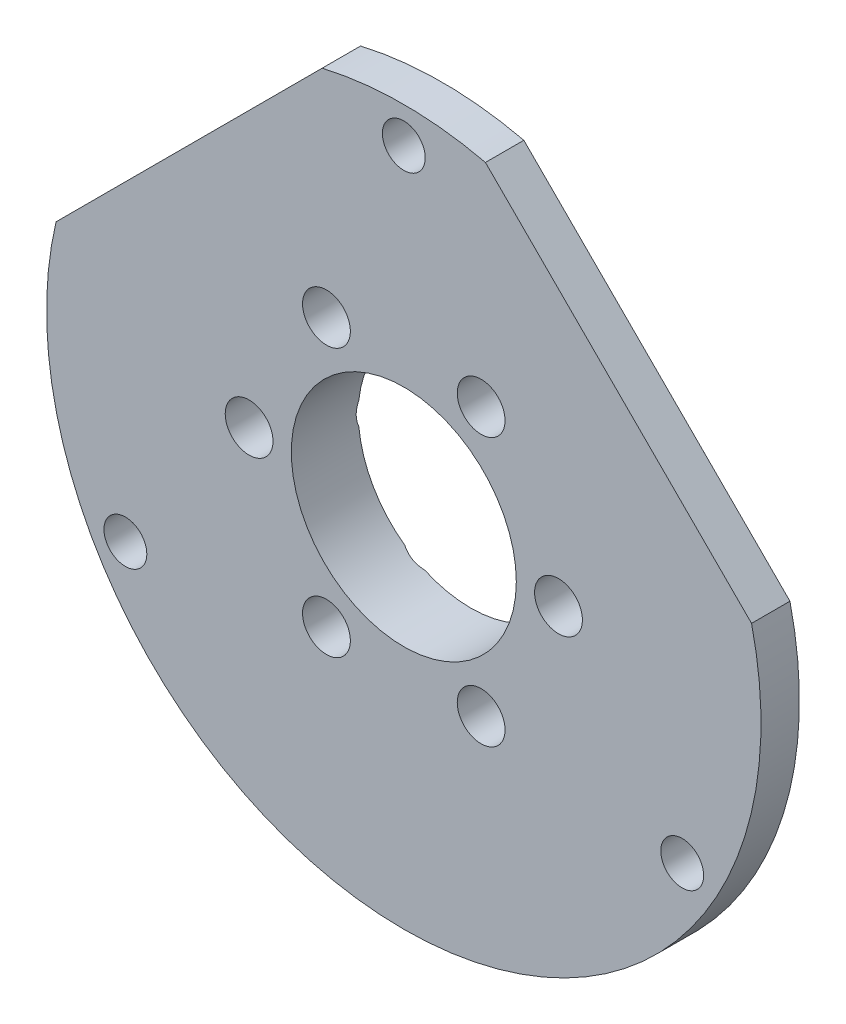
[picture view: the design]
ISO-10303-21;
HEADER;
FILE_DESCRIPTION(('STEP AP214'),'2;1');
FILE_NAME('part.step','',(''),(''),'','','');
FILE_SCHEMA(('AUTOMOTIVE_DESIGN { 1 0 10303 214 1 1 1 1 }'));
ENDSEC;
DATA;
#1=APPLICATION_CONTEXT('core data for automotive mechanical design processes');
#2=APPLICATION_PROTOCOL_DEFINITION('international standard','automotive_design',2000,#1);
#3=PRODUCT_CONTEXT('',#1,'mechanical');
#4=PRODUCT('Part','Part','',(#3));
#5=PRODUCT_RELATED_PRODUCT_CATEGORY('part','',(#4));
#6=PRODUCT_DEFINITION_FORMATION('','',#4);
#7=PRODUCT_DEFINITION_CONTEXT('part definition',#1,'design');
#8=PRODUCT_DEFINITION('design','',#6,#7);
#9=PRODUCT_DEFINITION_SHAPE('','',#8);
#10=(LENGTH_UNIT() NAMED_UNIT(*) SI_UNIT(.MILLI.,.METRE.));
#11=(NAMED_UNIT(*) PLANE_ANGLE_UNIT() SI_UNIT($,.RADIAN.));
#12=(NAMED_UNIT(*) SI_UNIT($,.STERADIAN.) SOLID_ANGLE_UNIT());
#13=UNCERTAINTY_MEASURE_WITH_UNIT(LENGTH_MEASURE(1.E-05),#10,'distance_accuracy_value','');
#14=(GEOMETRIC_REPRESENTATION_CONTEXT(3) GLOBAL_UNCERTAINTY_ASSIGNED_CONTEXT((#13)) GLOBAL_UNIT_ASSIGNED_CONTEXT((#10,
#11,#12)) REPRESENTATION_CONTEXT('',''));
#15=CARTESIAN_POINT('',(0.,0.,0.));
#16=DIRECTION('',(0.,0.,1.));
#17=DIRECTION('',(1.,0.,0.));
#18=AXIS2_PLACEMENT_3D('',#15,#16,#17);
#19=CARTESIAN_POINT('',(0.,0.,4.7625));
#20=DIRECTION('',(0.,0.,-1.));
#21=DIRECTION('',(-1.,0.,0.));
#22=AXIS2_PLACEMENT_3D('',#19,#20,#21);
#23=CYLINDRICAL_SURFACE('',#22,25.4);
#24=CARTESIAN_POINT('',(0.,0.,4.7625));
#25=DIRECTION('',(0.,0.,1.));
#26=DIRECTION('',(1.,0.,0.));
#27=AXIS2_PLACEMENT_3D('',#24,#25,#26);
#28=CIRCLE('',#27,25.4);
#29=CARTESIAN_POINT('',(-24.7277223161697,5.8051484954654,4.7625));
#30=VERTEX_POINT('',#29);
#31=CARTESIAN_POINT('',(24.7277223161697,5.8051484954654,4.7625));
#32=VERTEX_POINT('',#31);
#33=EDGE_CURVE('E136',#30,#32,#28,.T.);
#34=ORIENTED_EDGE('',*,*,#33,.F.);
#35=DIRECTION('',(0.,0.,-1.));
#36=VECTOR('',#35,1.);
#37=CARTESIAN_POINT('',(-24.7277223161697,5.80514849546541,4.7625));
#38=LINE('',#37,#36);
#39=CARTESIAN_POINT('',(-24.7277223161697,5.80514849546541,2.032));
#40=VERTEX_POINT('',#39);
#41=EDGE_CURVE('E120',#30,#40,#38,.T.);
#42=ORIENTED_EDGE('',*,*,#41,.T.);
#43=CARTESIAN_POINT('',(0.,0.,2.032));
#44=DIRECTION('',(0.,0.,-1.));
#45=DIRECTION('',(-1.,0.,0.));
#46=AXIS2_PLACEMENT_3D('',#43,#44,#45);
#47=CIRCLE('',#46,25.4);
#48=CARTESIAN_POINT('',(24.7277223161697,5.80514849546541,2.032));
#49=VERTEX_POINT('',#48);
#50=EDGE_CURVE('E198',#49,#40,#47,.T.);
#51=ORIENTED_EDGE('',*,*,#50,.F.);
#52=DIRECTION('',(0.,0.,-1.));
#53=VECTOR('',#52,1.);
#54=CARTESIAN_POINT('',(24.7277223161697,5.80514849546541,4.7625));
#55=LINE('',#54,#53);
#56=EDGE_CURVE('E66',#49,#32,#55,.F.);
#57=ORIENTED_EDGE('',*,*,#56,.T.);
#58=EDGE_LOOP('',(#34,#42,#51,#57));
#59=FACE_BOUND('',#58,.T.);
#60=ADVANCED_FACE('F43',(#59),#23,.T.);
#61=CARTESIAN_POINT('',(-5.8051484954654,24.7277223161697,2.032));
#62=VERTEX_POINT('',#61);
#63=CARTESIAN_POINT('',(5.8051484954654,24.7277223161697,2.032));
#64=VERTEX_POINT('',#63);
#65=EDGE_CURVE('E195',#62,#64,#47,.T.);
#66=ORIENTED_EDGE('',*,*,#65,.F.);
#67=DIRECTION('',(0.,0.,-1.));
#68=VECTOR('',#67,1.);
#69=CARTESIAN_POINT('',(-5.8051484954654,24.7277223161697,4.7625));
#70=LINE('',#69,#68);
#71=CARTESIAN_POINT('',(-5.8051484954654,24.7277223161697,4.7625));
#72=VERTEX_POINT('',#71);
#73=EDGE_CURVE('E58',#62,#72,#70,.F.);
#74=ORIENTED_EDGE('',*,*,#73,.T.);
#75=CARTESIAN_POINT('',(5.8051484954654,24.7277223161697,4.7625));
#76=VERTEX_POINT('',#75);
#77=EDGE_CURVE('E138',#76,#72,#28,.T.);
#78=ORIENTED_EDGE('',*,*,#77,.F.);
#79=DIRECTION('',(0.,0.,-1.));
#80=VECTOR('',#79,1.);
#81=CARTESIAN_POINT('',(5.8051484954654,24.7277223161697,4.7625));
#82=LINE('',#81,#80);
#83=EDGE_CURVE('E196',#76,#64,#82,.T.);
#84=ORIENTED_EDGE('',*,*,#83,.T.);
#85=EDGE_LOOP('',(#66,#74,#78,#84));
#86=FACE_BOUND('',#85,.T.);
#87=ADVANCED_FACE('F45',(#86),#23,.T.);
#88=CARTESIAN_POINT('',(0.,0.,0.));
#89=DIRECTION('',(0.,0.,1.));
#90=DIRECTION('',(1.,0.,0.));
#91=AXIS2_PLACEMENT_3D('',#88,#89,#90);
#92=PLANE('',#91);
#93=CARTESIAN_POINT('',(0.,0.,0.));
#94=DIRECTION('',(0.,0.,1.));
#95=DIRECTION('',(1.,0.,0.));
#96=AXIS2_PLACEMENT_3D('',#93,#94,#95);
#97=CIRCLE('',#96,17.907);
#98=CARTESIAN_POINT('',(17.907,0.,0.));
#99=VERTEX_POINT('',#98);
#100=EDGE_CURVE('E51',#99,#99,#97,.F.);
#101=ORIENTED_EDGE('',*,*,#100,.T.);
#102=EDGE_LOOP('',(#101));
#103=FACE_BOUND('',#102,.T.);
#104=CARTESIAN_POINT('',(0.,0.,0.));
#105=DIRECTION('',(0.,0.,1.));
#106=DIRECTION('',(1.,0.,0.));
#107=AXIS2_PLACEMENT_3D('',#104,#105,#106);
#108=CIRCLE('',#107,8.);
#109=CARTESIAN_POINT('',(-4.68745706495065,6.48288101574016,0.));
#110=VERTEX_POINT('',#109);
#111=CARTESIAN_POINT('',(-7.95806818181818,0.818016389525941,0.));
#112=VERTEX_POINT('',#111);
#113=EDGE_CURVE('E394',#110,#112,#108,.T.);
#114=ORIENTED_EDGE('',*,*,#113,.T.);
#115=CARTESIAN_POINT('',(-11.,0.,0.));
#116=DIRECTION('',(0.,0.,-1.));
#117=DIRECTION('',(-1.,0.,0.));
#118=AXIS2_PLACEMENT_3D('',#115,#116,#117);
#119=CIRCLE('',#118,3.15);
#120=CARTESIAN_POINT('',(-7.95806818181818,-0.818016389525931,0.));
#121=VERTEX_POINT('',#120);
#122=EDGE_CURVE('E201',#121,#112,#119,.T.);
#123=ORIENTED_EDGE('',*,*,#122,.F.);
#124=CARTESIAN_POINT('',(-4.68745706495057,-6.48288101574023,0.));
#125=VERTEX_POINT('',#124);
#126=EDGE_CURVE('E258',#121,#125,#108,.T.);
#127=ORIENTED_EDGE('',*,*,#126,.T.);
#128=CARTESIAN_POINT('',(-5.49999999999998,-9.52627944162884,0.));
#129=DIRECTION('',(0.,0.,-1.));
#130=DIRECTION('',(-1.,0.,0.));
#131=AXIS2_PLACEMENT_3D('',#128,#129,#130);
#132=CIRCLE('',#131,3.15);
#133=CARTESIAN_POINT('',(-3.27061111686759,-7.30089740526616,0.));
#134=VERTEX_POINT('',#133);
#135=EDGE_CURVE('E246',#134,#125,#132,.T.);
#136=ORIENTED_EDGE('',*,*,#135,.F.);
#137=CARTESIAN_POINT('',(3.27061111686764,-7.30089740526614,0.));
#138=VERTEX_POINT('',#137);
#139=EDGE_CURVE('E259',#134,#138,#108,.T.);
#140=ORIENTED_EDGE('',*,*,#139,.T.);
#141=CARTESIAN_POINT('',(5.50000000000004,-9.5262794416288,0.));
#142=DIRECTION('',(0.,0.,-1.));
#143=DIRECTION('',(-1.,0.,0.));
#144=AXIS2_PLACEMENT_3D('',#141,#142,#143);
#145=CIRCLE('',#144,3.15);
#146=CARTESIAN_POINT('',(4.6874570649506,-6.4828810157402,0.));
#147=VERTEX_POINT('',#146);
#148=EDGE_CURVE('E238',#147,#138,#145,.T.);
#149=ORIENTED_EDGE('',*,*,#148,.F.);
#150=CARTESIAN_POINT('',(7.95806818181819,-0.818016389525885,0.));
#151=VERTEX_POINT('',#150);
#152=EDGE_CURVE('E263',#147,#151,#108,.T.);
#153=ORIENTED_EDGE('',*,*,#152,.T.);
#154=CARTESIAN_POINT('',(11.,0.,0.));
#155=DIRECTION('',(0.,0.,-1.));
#156=DIRECTION('',(-1.,0.,0.));
#157=AXIS2_PLACEMENT_3D('',#154,#155,#156);
#158=CIRCLE('',#157,3.15);
#159=CARTESIAN_POINT('',(7.95806818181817,0.818016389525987,0.));
#160=VERTEX_POINT('',#159);
#161=EDGE_CURVE('E230',#160,#151,#158,.T.);
#162=ORIENTED_EDGE('',*,*,#161,.F.);
#163=CARTESIAN_POINT('',(4.68745706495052,6.48288101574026,0.));
#164=VERTEX_POINT('',#163);
#165=EDGE_CURVE('E398',#160,#164,#108,.T.);
#166=ORIENTED_EDGE('',*,*,#165,.T.);
#167=CARTESIAN_POINT('',(5.49999999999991,9.52627944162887,0.));
#168=DIRECTION('',(0.,0.,-1.));
#169=DIRECTION('',(-1.,0.,0.));
#170=AXIS2_PLACEMENT_3D('',#167,#168,#169);
#171=CIRCLE('',#170,3.15);
#172=CARTESIAN_POINT('',(3.27061111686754,7.30089740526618,0.));
#173=VERTEX_POINT('',#172);
#174=EDGE_CURVE('E222',#173,#164,#171,.T.);
#175=ORIENTED_EDGE('',*,*,#174,.F.);
#176=CARTESIAN_POINT('',(-3.27061111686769,7.30089740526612,0.));
#177=VERTEX_POINT('',#176);
#178=EDGE_CURVE('E395',#173,#177,#108,.T.);
#179=ORIENTED_EDGE('',*,*,#178,.T.);
#180=CARTESIAN_POINT('',(-5.50000000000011,9.52627944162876,0.));
#181=DIRECTION('',(0.,0.,-1.));
#182=DIRECTION('',(-1.,0.,0.));
#183=AXIS2_PLACEMENT_3D('',#180,#181,#182);
#184=CIRCLE('',#183,3.15);
#185=EDGE_CURVE('E214',#110,#177,#184,.T.);
#186=ORIENTED_EDGE('',*,*,#185,.F.);
#187=EDGE_LOOP('',(#114,#123,#127,#136,#140,#149,#153,#162,#166,#175,#179,#186));
#188=FACE_BOUND('',#187,.T.);
#189=ADVANCED_FACE('F185',(#103,#188),#92,.F.);
#190=CARTESIAN_POINT('',(19.7973407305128,-11.4299999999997,0.));
#191=DIRECTION('',(0.,0.,1.));
#192=DIRECTION('',(1.,0.,0.));
#193=AXIS2_PLACEMENT_3D('',#190,#191,#192);
#194=CYLINDRICAL_SURFACE('',#193,1.524);
#195=CARTESIAN_POINT('',(19.7973407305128,-11.4299999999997,4.7625));
#196=DIRECTION('',(0.,0.,1.));
#197=DIRECTION('',(1.,0.,0.));
#198=AXIS2_PLACEMENT_3D('',#195,#196,#197);
#199=CIRCLE('',#198,1.524);
#200=CARTESIAN_POINT('',(21.3213407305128,-11.4299999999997,4.7625));
#201=VERTEX_POINT('',#200);
#202=EDGE_CURVE('E140',#201,#201,#199,.T.);
#203=CARTESIAN_POINT('',(19.7973407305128,-11.4299999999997,2.032));
#204=DIRECTION('',(0.,0.,-1.));
#205=DIRECTION('',(-1.,0.,0.));
#206=AXIS2_PLACEMENT_3D('',#203,#204,#205);
#207=CIRCLE('',#206,1.524);
#208=CARTESIAN_POINT('',(21.3213407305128,-11.4299999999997,2.032));
#209=VERTEX_POINT('',#208);
#210=EDGE_CURVE('E199',#209,#209,#207,.F.);
#211=CARTESIAN_POINT('',(21.3213407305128,-11.4299999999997,4.7625));
#212=CARTESIAN_POINT('',(21.3213407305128,-11.4299999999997,4.73405729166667));
#213=CARTESIAN_POINT('',(21.3213407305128,-11.4299999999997,4.70561458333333));
#214=CARTESIAN_POINT('',(21.3213407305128,-11.4299999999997,4.64872916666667));
#215=CARTESIAN_POINT('',(21.3213407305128,-11.4299999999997,4.62028645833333));
#216=CARTESIAN_POINT('',(21.3213407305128,-11.4299999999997,4.56340104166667));
#217=CARTESIAN_POINT('',(21.3213407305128,-11.4299999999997,4.53495833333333));
#218=CARTESIAN_POINT('',(21.3213407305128,-11.4299999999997,4.47807291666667));
#219=CARTESIAN_POINT('',(21.3213407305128,-11.4299999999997,4.44963020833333));
#220=CARTESIAN_POINT('',(21.3213407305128,-11.4299999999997,4.39274479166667));
#221=CARTESIAN_POINT('',(21.3213407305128,-11.4299999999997,4.36430208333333));
#222=CARTESIAN_POINT('',(21.3213407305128,-11.4299999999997,4.30741666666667));
#223=CARTESIAN_POINT('',(21.3213407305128,-11.4299999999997,4.27897395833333));
#224=CARTESIAN_POINT('',(21.3213407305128,-11.4299999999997,4.22208854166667));
#225=CARTESIAN_POINT('',(21.3213407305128,-11.4299999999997,4.19364583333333));
#226=CARTESIAN_POINT('',(21.3213407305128,-11.4299999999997,4.13676041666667));
#227=CARTESIAN_POINT('',(21.3213407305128,-11.4299999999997,4.10831770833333));
#228=CARTESIAN_POINT('',(21.3213407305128,-11.4299999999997,4.05143229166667));
#229=CARTESIAN_POINT('',(21.3213407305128,-11.4299999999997,4.02298958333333));
#230=CARTESIAN_POINT('',(21.3213407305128,-11.4299999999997,3.96610416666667));
#231=CARTESIAN_POINT('',(21.3213407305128,-11.4299999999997,3.93766145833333));
#232=CARTESIAN_POINT('',(21.3213407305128,-11.4299999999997,3.88077604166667));
#233=CARTESIAN_POINT('',(21.3213407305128,-11.4299999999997,3.85233333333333));
#234=CARTESIAN_POINT('',(21.3213407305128,-11.4299999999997,3.79544791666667));
#235=CARTESIAN_POINT('',(21.3213407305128,-11.4299999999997,3.76700520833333));
#236=CARTESIAN_POINT('',(21.3213407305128,-11.4299999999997,3.71011979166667));
#237=CARTESIAN_POINT('',(21.3213407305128,-11.4299999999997,3.68167708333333));
#238=CARTESIAN_POINT('',(21.3213407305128,-11.4299999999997,3.62479166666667));
#239=CARTESIAN_POINT('',(21.3213407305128,-11.4299999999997,3.59634895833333));
#240=CARTESIAN_POINT('',(21.3213407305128,-11.4299999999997,3.53946354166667));
#241=CARTESIAN_POINT('',(21.3213407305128,-11.4299999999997,3.51102083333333));
#242=CARTESIAN_POINT('',(21.3213407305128,-11.4299999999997,3.45413541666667));
#243=CARTESIAN_POINT('',(21.3213407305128,-11.4299999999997,3.42569270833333));
#244=CARTESIAN_POINT('',(21.3213407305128,-11.4299999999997,3.36880729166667));
#245=CARTESIAN_POINT('',(21.3213407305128,-11.4299999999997,3.34036458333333));
#246=CARTESIAN_POINT('',(21.3213407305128,-11.4299999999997,3.28347916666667));
#247=CARTESIAN_POINT('',(21.3213407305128,-11.4299999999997,3.25503645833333));
#248=CARTESIAN_POINT('',(21.3213407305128,-11.4299999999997,3.19815104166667));
#249=CARTESIAN_POINT('',(21.3213407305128,-11.4299999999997,3.16970833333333));
#250=CARTESIAN_POINT('',(21.3213407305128,-11.4299999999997,3.11282291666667));
#251=CARTESIAN_POINT('',(21.3213407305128,-11.4299999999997,3.08438020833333));
#252=CARTESIAN_POINT('',(21.3213407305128,-11.4299999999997,3.02749479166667));
#253=CARTESIAN_POINT('',(21.3213407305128,-11.4299999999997,2.99905208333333));
#254=CARTESIAN_POINT('',(21.3213407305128,-11.4299999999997,2.94216666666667));
#255=CARTESIAN_POINT('',(21.3213407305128,-11.4299999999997,2.91372395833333));
#256=CARTESIAN_POINT('',(21.3213407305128,-11.4299999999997,2.85683854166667));
#257=CARTESIAN_POINT('',(21.3213407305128,-11.4299999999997,2.82839583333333));
#258=CARTESIAN_POINT('',(21.3213407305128,-11.4299999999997,2.77151041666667));
#259=CARTESIAN_POINT('',(21.3213407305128,-11.4299999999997,2.74306770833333));
#260=CARTESIAN_POINT('',(21.3213407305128,-11.4299999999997,2.68618229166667));
#261=CARTESIAN_POINT('',(21.3213407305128,-11.4299999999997,2.65773958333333));
#262=CARTESIAN_POINT('',(21.3213407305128,-11.4299999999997,2.60085416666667));
#263=CARTESIAN_POINT('',(21.3213407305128,-11.4299999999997,2.57241145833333));
#264=CARTESIAN_POINT('',(21.3213407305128,-11.4299999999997,2.51552604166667));
#265=CARTESIAN_POINT('',(21.3213407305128,-11.4299999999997,2.48708333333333));
#266=CARTESIAN_POINT('',(21.3213407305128,-11.4299999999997,2.43019791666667));
#267=CARTESIAN_POINT('',(21.3213407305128,-11.4299999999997,2.40175520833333));
#268=CARTESIAN_POINT('',(21.3213407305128,-11.4299999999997,2.34486979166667));
#269=CARTESIAN_POINT('',(21.3213407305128,-11.4299999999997,2.31642708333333));
#270=CARTESIAN_POINT('',(21.3213407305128,-11.4299999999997,2.25954166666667));
#271=CARTESIAN_POINT('',(21.3213407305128,-11.4299999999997,2.23109895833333));
#272=CARTESIAN_POINT('',(21.3213407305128,-11.4299999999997,2.17421354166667));
#273=CARTESIAN_POINT('',(21.3213407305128,-11.4299999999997,2.14577083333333));
#274=CARTESIAN_POINT('',(21.3213407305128,-11.4299999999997,2.08888541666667));
#275=CARTESIAN_POINT('',(21.3213407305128,-11.4299999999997,2.06044270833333));
#276=CARTESIAN_POINT('',(21.3213407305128,-11.4299999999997,2.032));
#277=B_SPLINE_CURVE_WITH_KNOTS('',3,(#211,#212,#213,#214,#215,#216,#217,#218,#219,#220,#221,
#222,#223,#224,#225,#226,#227,#228,#229,#230,#231,#232,#233,#234,#235,#236,#237,#238,#239,#240,
#241,#242,#243,#244,#245,#246,#247,#248,#249,#250,#251,#252,#253,#254,#255,#256,#257,#258,#259,
#260,#261,#262,#263,#264,#265,#266,#267,#268,#269,#270,#271,#272,#273,#274,#275,#276),
.UNSPECIFIED.,.F.,.F.,(4,2,2,2,2,2,2,2,2,2,2,2,2,2,2,2,2,2,2,2,2,2,2,2,2,2,2,2,2,2,2,2,4),(0.,
0.0853281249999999,0.17065625,0.255984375,0.3413125,0.426640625,0.51196875,0.597296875,0.682625,
0.767953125,0.85328125,0.938609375,1.0239375,1.109265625,1.19459375,1.279921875,1.36525,
1.450578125,1.53590625,1.621234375,1.7065625,1.791890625,1.87721875,1.962546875,2.047875,
2.133203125,2.21853125,2.303859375,2.3891875,2.474515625,2.55984375,2.645171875,2.7305),.UNSPECIFIED.);
#278=EDGE_CURVE('BSEAM190',#201,#209,#277,.T.);
#279=ORIENTED_EDGE('',*,*,#202,.T.);
#280=ORIENTED_EDGE('',*,*,#210,.F.);
#281=ORIENTED_EDGE('',*,*,#278,.T.);
#282=ORIENTED_EDGE('',*,*,#278,.F.);
#283=EDGE_LOOP('',(#279,#281,#280,#282));
#284=FACE_BOUND('',#283,.T.);
#285=ADVANCED_FACE('F190',(#284),#194,.F.);
#286=CARTESIAN_POINT('',(-19.7973407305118,-11.4300000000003,0.));
#287=DIRECTION('',(0.,0.,1.));
#288=DIRECTION('',(1.,0.,0.));
#289=AXIS2_PLACEMENT_3D('',#286,#287,#288);
#290=CYLINDRICAL_SURFACE('',#289,1.524);
#291=CARTESIAN_POINT('',(-19.7973407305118,-11.4300000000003,4.7625));
#292=DIRECTION('',(0.,0.,1.));
#293=DIRECTION('',(1.,0.,0.));
#294=AXIS2_PLACEMENT_3D('',#291,#292,#293);
#295=CIRCLE('',#294,1.524);
#296=CARTESIAN_POINT('',(-18.2733407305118,-11.4300000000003,4.7625));
#297=VERTEX_POINT('',#296);
#298=EDGE_CURVE('E144',#297,#297,#295,.T.);
#299=CARTESIAN_POINT('',(-19.7973407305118,-11.4300000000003,2.032));
#300=DIRECTION('',(0.,0.,-1.));
#301=DIRECTION('',(-1.,0.,0.));
#302=AXIS2_PLACEMENT_3D('',#299,#300,#301);
#303=CIRCLE('',#302,1.524);
#304=CARTESIAN_POINT('',(-18.2733407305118,-11.4300000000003,2.032));
#305=VERTEX_POINT('',#304);
#306=EDGE_CURVE('E203',#305,#305,#303,.F.);
#307=CARTESIAN_POINT('',(-18.2733407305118,-11.4300000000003,4.7625));
#308=CARTESIAN_POINT('',(-18.2733407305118,-11.4300000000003,4.73405729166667));
#309=CARTESIAN_POINT('',(-18.2733407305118,-11.4300000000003,4.70561458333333));
#310=CARTESIAN_POINT('',(-18.2733407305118,-11.4300000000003,4.64872916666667));
#311=CARTESIAN_POINT('',(-18.2733407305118,-11.4300000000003,4.62028645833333));
#312=CARTESIAN_POINT('',(-18.2733407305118,-11.4300000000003,4.56340104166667));
#313=CARTESIAN_POINT('',(-18.2733407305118,-11.4300000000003,4.53495833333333));
#314=CARTESIAN_POINT('',(-18.2733407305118,-11.4300000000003,4.47807291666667));
#315=CARTESIAN_POINT('',(-18.2733407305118,-11.4300000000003,4.44963020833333));
#316=CARTESIAN_POINT('',(-18.2733407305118,-11.4300000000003,4.39274479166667));
#317=CARTESIAN_POINT('',(-18.2733407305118,-11.4300000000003,4.36430208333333));
#318=CARTESIAN_POINT('',(-18.2733407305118,-11.4300000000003,4.30741666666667));
#319=CARTESIAN_POINT('',(-18.2733407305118,-11.4300000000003,4.27897395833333));
#320=CARTESIAN_POINT('',(-18.2733407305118,-11.4300000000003,4.22208854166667));
#321=CARTESIAN_POINT('',(-18.2733407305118,-11.4300000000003,4.19364583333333));
#322=CARTESIAN_POINT('',(-18.2733407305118,-11.4300000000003,4.13676041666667));
#323=CARTESIAN_POINT('',(-18.2733407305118,-11.4300000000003,4.10831770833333));
#324=CARTESIAN_POINT('',(-18.2733407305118,-11.4300000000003,4.05143229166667));
#325=CARTESIAN_POINT('',(-18.2733407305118,-11.4300000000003,4.02298958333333));
#326=CARTESIAN_POINT('',(-18.2733407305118,-11.4300000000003,3.96610416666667));
#327=CARTESIAN_POINT('',(-18.2733407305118,-11.4300000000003,3.93766145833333));
#328=CARTESIAN_POINT('',(-18.2733407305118,-11.4300000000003,3.88077604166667));
#329=CARTESIAN_POINT('',(-18.2733407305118,-11.4300000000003,3.85233333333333));
#330=CARTESIAN_POINT('',(-18.2733407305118,-11.4300000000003,3.79544791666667));
#331=CARTESIAN_POINT('',(-18.2733407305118,-11.4300000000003,3.76700520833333));
#332=CARTESIAN_POINT('',(-18.2733407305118,-11.4300000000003,3.71011979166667));
#333=CARTESIAN_POINT('',(-18.2733407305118,-11.4300000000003,3.68167708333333));
#334=CARTESIAN_POINT('',(-18.2733407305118,-11.4300000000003,3.62479166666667));
#335=CARTESIAN_POINT('',(-18.2733407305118,-11.4300000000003,3.59634895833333));
#336=CARTESIAN_POINT('',(-18.2733407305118,-11.4300000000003,3.53946354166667));
#337=CARTESIAN_POINT('',(-18.2733407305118,-11.4300000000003,3.51102083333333));
#338=CARTESIAN_POINT('',(-18.2733407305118,-11.4300000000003,3.45413541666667));
#339=CARTESIAN_POINT('',(-18.2733407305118,-11.4300000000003,3.42569270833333));
#340=CARTESIAN_POINT('',(-18.2733407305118,-11.4300000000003,3.36880729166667));
#341=CARTESIAN_POINT('',(-18.2733407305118,-11.4300000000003,3.34036458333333));
#342=CARTESIAN_POINT('',(-18.2733407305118,-11.4300000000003,3.28347916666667));
#343=CARTESIAN_POINT('',(-18.2733407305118,-11.4300000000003,3.25503645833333));
#344=CARTESIAN_POINT('',(-18.2733407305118,-11.4300000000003,3.19815104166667));
#345=CARTESIAN_POINT('',(-18.2733407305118,-11.4300000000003,3.16970833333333));
#346=CARTESIAN_POINT('',(-18.2733407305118,-11.4300000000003,3.11282291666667));
#347=CARTESIAN_POINT('',(-18.2733407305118,-11.4300000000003,3.08438020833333));
#348=CARTESIAN_POINT('',(-18.2733407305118,-11.4300000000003,3.02749479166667));
#349=CARTESIAN_POINT('',(-18.2733407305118,-11.4300000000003,2.99905208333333));
#350=CARTESIAN_POINT('',(-18.2733407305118,-11.4300000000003,2.94216666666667));
#351=CARTESIAN_POINT('',(-18.2733407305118,-11.4300000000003,2.91372395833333));
#352=CARTESIAN_POINT('',(-18.2733407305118,-11.4300000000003,2.85683854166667));
#353=CARTESIAN_POINT('',(-18.2733407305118,-11.4300000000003,2.82839583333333));
#354=CARTESIAN_POINT('',(-18.2733407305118,-11.4300000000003,2.77151041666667));
#355=CARTESIAN_POINT('',(-18.2733407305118,-11.4300000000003,2.74306770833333));
#356=CARTESIAN_POINT('',(-18.2733407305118,-11.4300000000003,2.68618229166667));
#357=CARTESIAN_POINT('',(-18.2733407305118,-11.4300000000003,2.65773958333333));
#358=CARTESIAN_POINT('',(-18.2733407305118,-11.4300000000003,2.60085416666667));
#359=CARTESIAN_POINT('',(-18.2733407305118,-11.4300000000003,2.57241145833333));
#360=CARTESIAN_POINT('',(-18.2733407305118,-11.4300000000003,2.51552604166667));
#361=CARTESIAN_POINT('',(-18.2733407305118,-11.4300000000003,2.48708333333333));
#362=CARTESIAN_POINT('',(-18.2733407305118,-11.4300000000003,2.43019791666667));
#363=CARTESIAN_POINT('',(-18.2733407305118,-11.4300000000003,2.40175520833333));
#364=CARTESIAN_POINT('',(-18.2733407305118,-11.4300000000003,2.34486979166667));
#365=CARTESIAN_POINT('',(-18.2733407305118,-11.4300000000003,2.31642708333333));
#366=CARTESIAN_POINT('',(-18.2733407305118,-11.4300000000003,2.25954166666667));
#367=CARTESIAN_POINT('',(-18.2733407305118,-11.4300000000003,2.23109895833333));
#368=CARTESIAN_POINT('',(-18.2733407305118,-11.4300000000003,2.17421354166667));
#369=CARTESIAN_POINT('',(-18.2733407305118,-11.4300000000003,2.14577083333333));
#370=CARTESIAN_POINT('',(-18.2733407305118,-11.4300000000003,2.08888541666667));
#371=CARTESIAN_POINT('',(-18.2733407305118,-11.4300000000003,2.06044270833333));
#372=CARTESIAN_POINT('',(-18.2733407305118,-11.4300000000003,2.032));
#373=B_SPLINE_CURVE_WITH_KNOTS('',3,(#307,#308,#309,#310,#311,#312,#313,#314,#315,#316,#317,
#318,#319,#320,#321,#322,#323,#324,#325,#326,#327,#328,#329,#330,#331,#332,#333,#334,#335,#336,
#337,#338,#339,#340,#341,#342,#343,#344,#345,#346,#347,#348,#349,#350,#351,#352,#353,#354,#355,
#356,#357,#358,#359,#360,#361,#362,#363,#364,#365,#366,#367,#368,#369,#370,#371,#372),
.UNSPECIFIED.,.F.,.F.,(4,2,2,2,2,2,2,2,2,2,2,2,2,2,2,2,2,2,2,2,2,2,2,2,2,2,2,2,2,2,2,2,4),(0.,
0.0853281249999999,0.17065625,0.255984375,0.3413125,0.426640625,0.51196875,0.597296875,0.682625,
0.767953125,0.85328125,0.938609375,1.0239375,1.109265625,1.19459375,1.279921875,1.36525,
1.450578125,1.53590625,1.621234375,1.7065625,1.791890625,1.87721875,1.962546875,2.047875,
2.133203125,2.21853125,2.303859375,2.3891875,2.474515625,2.55984375,2.645171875,2.7305),.UNSPECIFIED.);
#374=EDGE_CURVE('BSEAM268',#297,#305,#373,.T.);
#375=ORIENTED_EDGE('',*,*,#298,.T.);
#376=ORIENTED_EDGE('',*,*,#306,.F.);
#377=ORIENTED_EDGE('',*,*,#374,.T.);
#378=ORIENTED_EDGE('',*,*,#374,.F.);
#379=EDGE_LOOP('',(#375,#377,#376,#378));
#380=FACE_BOUND('',#379,.T.);
#381=ADVANCED_FACE('F268',(#380),#290,.F.);
#382=CARTESIAN_POINT('',(0.,22.8599999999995,0.));
#383=DIRECTION('',(0.,0.,1.));
#384=DIRECTION('',(1.,0.,0.));
#385=AXIS2_PLACEMENT_3D('',#382,#383,#384);
#386=CYLINDRICAL_SURFACE('',#385,1.524);
#387=CARTESIAN_POINT('',(0.,22.8599999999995,4.7625));
#388=DIRECTION('',(0.,0.,1.));
#389=DIRECTION('',(1.,0.,0.));
#390=AXIS2_PLACEMENT_3D('',#387,#388,#389);
#391=CIRCLE('',#390,1.524);
#392=CARTESIAN_POINT('',(1.524,22.8599999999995,4.7625));
#393=VERTEX_POINT('',#392);
#394=EDGE_CURVE('E262',#393,#393,#391,.T.);
#395=CARTESIAN_POINT('',(0.,22.8599999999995,2.032));
#396=DIRECTION('',(0.,0.,-1.));
#397=DIRECTION('',(-1.,0.,0.));
#398=AXIS2_PLACEMENT_3D('',#395,#396,#397);
#399=CIRCLE('',#398,1.524);
#400=CARTESIAN_POINT('',(1.524,22.8599999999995,2.032));
#401=VERTEX_POINT('',#400);
#402=EDGE_CURVE('E290',#401,#401,#399,.F.);
#403=CARTESIAN_POINT('',(1.524,22.8599999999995,4.7625));
#404=CARTESIAN_POINT('',(1.524,22.8599999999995,4.73405729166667));
#405=CARTESIAN_POINT('',(1.524,22.8599999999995,4.70561458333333));
#406=CARTESIAN_POINT('',(1.524,22.8599999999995,4.64872916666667));
#407=CARTESIAN_POINT('',(1.524,22.8599999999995,4.62028645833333));
#408=CARTESIAN_POINT('',(1.524,22.8599999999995,4.56340104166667));
#409=CARTESIAN_POINT('',(1.524,22.8599999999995,4.53495833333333));
#410=CARTESIAN_POINT('',(1.524,22.8599999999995,4.47807291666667));
#411=CARTESIAN_POINT('',(1.524,22.8599999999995,4.44963020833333));
#412=CARTESIAN_POINT('',(1.524,22.8599999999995,4.39274479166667));
#413=CARTESIAN_POINT('',(1.524,22.8599999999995,4.36430208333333));
#414=CARTESIAN_POINT('',(1.524,22.8599999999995,4.30741666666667));
#415=CARTESIAN_POINT('',(1.524,22.8599999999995,4.27897395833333));
#416=CARTESIAN_POINT('',(1.524,22.8599999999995,4.22208854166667));
#417=CARTESIAN_POINT('',(1.524,22.8599999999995,4.19364583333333));
#418=CARTESIAN_POINT('',(1.524,22.8599999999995,4.13676041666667));
#419=CARTESIAN_POINT('',(1.524,22.8599999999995,4.10831770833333));
#420=CARTESIAN_POINT('',(1.524,22.8599999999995,4.05143229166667));
#421=CARTESIAN_POINT('',(1.524,22.8599999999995,4.02298958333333));
#422=CARTESIAN_POINT('',(1.524,22.8599999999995,3.96610416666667));
#423=CARTESIAN_POINT('',(1.524,22.8599999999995,3.93766145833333));
#424=CARTESIAN_POINT('',(1.524,22.8599999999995,3.88077604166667));
#425=CARTESIAN_POINT('',(1.524,22.8599999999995,3.85233333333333));
#426=CARTESIAN_POINT('',(1.524,22.8599999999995,3.79544791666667));
#427=CARTESIAN_POINT('',(1.524,22.8599999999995,3.76700520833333));
#428=CARTESIAN_POINT('',(1.524,22.8599999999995,3.71011979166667));
#429=CARTESIAN_POINT('',(1.524,22.8599999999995,3.68167708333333));
#430=CARTESIAN_POINT('',(1.524,22.8599999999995,3.62479166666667));
#431=CARTESIAN_POINT('',(1.524,22.8599999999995,3.59634895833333));
#432=CARTESIAN_POINT('',(1.524,22.8599999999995,3.53946354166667));
#433=CARTESIAN_POINT('',(1.524,22.8599999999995,3.51102083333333));
#434=CARTESIAN_POINT('',(1.524,22.8599999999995,3.45413541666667));
#435=CARTESIAN_POINT('',(1.524,22.8599999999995,3.42569270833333));
#436=CARTESIAN_POINT('',(1.524,22.8599999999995,3.36880729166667));
#437=CARTESIAN_POINT('',(1.524,22.8599999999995,3.34036458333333));
#438=CARTESIAN_POINT('',(1.524,22.8599999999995,3.28347916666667));
#439=CARTESIAN_POINT('',(1.524,22.8599999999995,3.25503645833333));
#440=CARTESIAN_POINT('',(1.524,22.8599999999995,3.19815104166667));
#441=CARTESIAN_POINT('',(1.524,22.8599999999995,3.16970833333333));
#442=CARTESIAN_POINT('',(1.524,22.8599999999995,3.11282291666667));
#443=CARTESIAN_POINT('',(1.524,22.8599999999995,3.08438020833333));
#444=CARTESIAN_POINT('',(1.524,22.8599999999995,3.02749479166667));
#445=CARTESIAN_POINT('',(1.524,22.8599999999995,2.99905208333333));
#446=CARTESIAN_POINT('',(1.524,22.8599999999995,2.94216666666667));
#447=CARTESIAN_POINT('',(1.524,22.8599999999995,2.91372395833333));
#448=CARTESIAN_POINT('',(1.524,22.8599999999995,2.85683854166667));
#449=CARTESIAN_POINT('',(1.524,22.8599999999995,2.82839583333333));
#450=CARTESIAN_POINT('',(1.524,22.8599999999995,2.77151041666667));
#451=CARTESIAN_POINT('',(1.524,22.8599999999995,2.74306770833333));
#452=CARTESIAN_POINT('',(1.524,22.8599999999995,2.68618229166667));
#453=CARTESIAN_POINT('',(1.524,22.8599999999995,2.65773958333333));
#454=CARTESIAN_POINT('',(1.524,22.8599999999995,2.60085416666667));
#455=CARTESIAN_POINT('',(1.524,22.8599999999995,2.57241145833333));
#456=CARTESIAN_POINT('',(1.524,22.8599999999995,2.51552604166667));
#457=CARTESIAN_POINT('',(1.524,22.8599999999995,2.48708333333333));
#458=CARTESIAN_POINT('',(1.524,22.8599999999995,2.43019791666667));
#459=CARTESIAN_POINT('',(1.524,22.8599999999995,2.40175520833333));
#460=CARTESIAN_POINT('',(1.524,22.8599999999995,2.34486979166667));
#461=CARTESIAN_POINT('',(1.524,22.8599999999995,2.31642708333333));
#462=CARTESIAN_POINT('',(1.524,22.8599999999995,2.25954166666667));
#463=CARTESIAN_POINT('',(1.524,22.8599999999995,2.23109895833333));
#464=CARTESIAN_POINT('',(1.524,22.8599999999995,2.17421354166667));
#465=CARTESIAN_POINT('',(1.524,22.8599999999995,2.14577083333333));
#466=CARTESIAN_POINT('',(1.524,22.8599999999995,2.08888541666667));
#467=CARTESIAN_POINT('',(1.524,22.8599999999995,2.06044270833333));
#468=CARTESIAN_POINT('',(1.524,22.8599999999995,2.032));
#469=B_SPLINE_CURVE_WITH_KNOTS('',3,(#403,#404,#405,#406,#407,#408,#409,#410,#411,#412,#413,
#414,#415,#416,#417,#418,#419,#420,#421,#422,#423,#424,#425,#426,#427,#428,#429,#430,#431,#432,
#433,#434,#435,#436,#437,#438,#439,#440,#441,#442,#443,#444,#445,#446,#447,#448,#449,#450,#451,
#452,#453,#454,#455,#456,#457,#458,#459,#460,#461,#462,#463,#464,#465,#466,#467,#468),
.UNSPECIFIED.,.F.,.F.,(4,2,2,2,2,2,2,2,2,2,2,2,2,2,2,2,2,2,2,2,2,2,2,2,2,2,2,2,2,2,2,2,4),(0.,
0.0853281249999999,0.17065625,0.255984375,0.3413125,0.426640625,0.51196875,0.597296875,0.682625,
0.767953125,0.85328125,0.938609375,1.0239375,1.109265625,1.19459375,1.279921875,1.36525,
1.450578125,1.53590625,1.621234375,1.7065625,1.791890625,1.87721875,1.962546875,2.047875,
2.133203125,2.21853125,2.303859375,2.3891875,2.474515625,2.55984375,2.645171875,2.7305),.UNSPECIFIED.);
#470=EDGE_CURVE('BSEAM273',#393,#401,#469,.T.);
#471=ORIENTED_EDGE('',*,*,#394,.T.);
#472=ORIENTED_EDGE('',*,*,#402,.F.);
#473=ORIENTED_EDGE('',*,*,#470,.T.);
#474=ORIENTED_EDGE('',*,*,#470,.F.);
#475=EDGE_LOOP('',(#471,#473,#472,#474));
#476=FACE_BOUND('',#475,.T.);
#477=ADVANCED_FACE('F273',(#476),#386,.F.);
#478=CARTESIAN_POINT('',(0.,0.,4.7625));
#479=DIRECTION('',(0.,0.,1.));
#480=DIRECTION('',(1.,0.,0.));
#481=AXIS2_PLACEMENT_3D('',#478,#479,#480);
#482=PLANE('',#481);
#483=DIRECTION('',(0.707106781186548,0.707106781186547,0.));
#484=VECTOR('',#483,1.);
#485=CARTESIAN_POINT('',(-3.61076745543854,26.9221033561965,4.7625));
#486=LINE('',#485,#484);
#487=EDGE_CURVE('E123',#30,#72,#486,.T.);
#488=ORIENTED_EDGE('',*,*,#487,.F.);
#489=ORIENTED_EDGE('',*,*,#33,.T.);
#490=DIRECTION('',(0.707106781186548,-0.707106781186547,0.));
#491=VECTOR('',#490,1.);
#492=CARTESIAN_POINT('',(3.61076745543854,26.9221033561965,4.7625));
#493=LINE('',#492,#491);
#494=EDGE_CURVE('E129',#76,#32,#493,.T.);
#495=ORIENTED_EDGE('',*,*,#494,.F.);
#496=ORIENTED_EDGE('',*,*,#77,.T.);
#497=EDGE_LOOP('',(#488,#489,#495,#496));
#498=FACE_BOUND('',#497,.T.);
#499=CARTESIAN_POINT('',(-11.,0.,4.7625));
#500=DIRECTION('',(0.,0.,-1.));
#501=DIRECTION('',(-1.,0.,0.));
#502=AXIS2_PLACEMENT_3D('',#499,#500,#501);
#503=CIRCLE('',#502,1.7);
#504=CARTESIAN_POINT('',(-12.7,0.,4.7625));
#505=VERTEX_POINT('',#504);
#506=EDGE_CURVE('E211',#505,#505,#503,.T.);
#507=ORIENTED_EDGE('',*,*,#506,.T.);
#508=EDGE_LOOP('',(#507));
#509=FACE_BOUND('',#508,.T.);
#510=CARTESIAN_POINT('',(-5.50000000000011,9.52627944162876,4.7625));
#511=DIRECTION('',(0.,0.,-1.));
#512=DIRECTION('',(-1.,0.,0.));
#513=AXIS2_PLACEMENT_3D('',#510,#511,#512);
#514=CIRCLE('',#513,1.7);
#515=CARTESIAN_POINT('',(-7.20000000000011,9.52627944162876,4.7625));
#516=VERTEX_POINT('',#515);
#517=EDGE_CURVE('E219',#516,#516,#514,.T.);
#518=ORIENTED_EDGE('',*,*,#517,.T.);
#519=EDGE_LOOP('',(#518));
#520=FACE_BOUND('',#519,.T.);
#521=CARTESIAN_POINT('',(5.49999999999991,9.52627944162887,4.7625));
#522=DIRECTION('',(0.,0.,-1.));
#523=DIRECTION('',(-1.,0.,0.));
#524=AXIS2_PLACEMENT_3D('',#521,#522,#523);
#525=CIRCLE('',#524,1.7);
#526=CARTESIAN_POINT('',(3.79999999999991,9.52627944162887,4.7625));
#527=VERTEX_POINT('',#526);
#528=EDGE_CURVE('E227',#527,#527,#525,.T.);
#529=ORIENTED_EDGE('',*,*,#528,.T.);
#530=EDGE_LOOP('',(#529));
#531=FACE_BOUND('',#530,.T.);
#532=CARTESIAN_POINT('',(11.,0.,4.7625));
#533=DIRECTION('',(0.,0.,-1.));
#534=DIRECTION('',(-1.,0.,0.));
#535=AXIS2_PLACEMENT_3D('',#532,#533,#534);
#536=CIRCLE('',#535,1.7);
#537=CARTESIAN_POINT('',(9.3,0.,4.7625));
#538=VERTEX_POINT('',#537);
#539=EDGE_CURVE('E235',#538,#538,#536,.T.);
#540=ORIENTED_EDGE('',*,*,#539,.T.);
#541=EDGE_LOOP('',(#540));
#542=FACE_BOUND('',#541,.T.);
#543=CARTESIAN_POINT('',(5.50000000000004,-9.5262794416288,4.7625));
#544=DIRECTION('',(0.,0.,-1.));
#545=DIRECTION('',(-1.,0.,0.));
#546=AXIS2_PLACEMENT_3D('',#543,#544,#545);
#547=CIRCLE('',#546,1.7);
#548=CARTESIAN_POINT('',(3.80000000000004,-9.5262794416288,4.7625));
#549=VERTEX_POINT('',#548);
#550=EDGE_CURVE('E243',#549,#549,#547,.T.);
#551=ORIENTED_EDGE('',*,*,#550,.T.);
#552=EDGE_LOOP('',(#551));
#553=FACE_BOUND('',#552,.T.);
#554=CARTESIAN_POINT('',(-5.49999999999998,-9.52627944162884,4.7625));
#555=DIRECTION('',(0.,0.,-1.));
#556=DIRECTION('',(-1.,0.,0.));
#557=AXIS2_PLACEMENT_3D('',#554,#555,#556);
#558=CIRCLE('',#557,1.7);
#559=CARTESIAN_POINT('',(-7.19999999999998,-9.52627944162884,4.7625));
#560=VERTEX_POINT('',#559);
#561=EDGE_CURVE('E252',#560,#560,#558,.T.);
#562=ORIENTED_EDGE('',*,*,#561,.T.);
#563=EDGE_LOOP('',(#562));
#564=FACE_BOUND('',#563,.T.);
#565=CARTESIAN_POINT('',(0.,0.,4.7625));
#566=DIRECTION('',(0.,0.,1.));
#567=DIRECTION('',(1.,0.,0.));
#568=AXIS2_PLACEMENT_3D('',#565,#566,#567);
#569=CIRCLE('',#568,8.);
#570=CARTESIAN_POINT('',(8.,0.,4.7625));
#571=VERTEX_POINT('',#570);
#572=EDGE_CURVE('E255',#571,#571,#569,.T.);
#573=ORIENTED_EDGE('',*,*,#572,.F.);
#574=EDGE_LOOP('',(#573));
#575=FACE_BOUND('',#574,.T.);
#576=ORIENTED_EDGE('',*,*,#394,.F.);
#577=EDGE_LOOP('',(#576));
#578=FACE_BOUND('',#577,.T.);
#579=ORIENTED_EDGE('',*,*,#298,.F.);
#580=EDGE_LOOP('',(#579));
#581=FACE_BOUND('',#580,.T.);
#582=ORIENTED_EDGE('',*,*,#202,.F.);
#583=EDGE_LOOP('',(#582));
#584=FACE_BOUND('',#583,.T.);
#585=ADVANCED_FACE('F133',(#498,#509,#520,#531,#542,#553,#564,#575,#578,#581,#584),#482,.T.);
#586=CARTESIAN_POINT('',(0.,0.,0.));
#587=DIRECTION('',(0.,0.,1.));
#588=DIRECTION('',(1.,0.,0.));
#589=AXIS2_PLACEMENT_3D('',#586,#587,#588);
#590=CYLINDRICAL_SURFACE('',#589,8.);
#591=ORIENTED_EDGE('',*,*,#126,.F.);
#592=CARTESIAN_POINT('',(-7.95801090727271,-0.818573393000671,-0.000200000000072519));
#593=CARTESIAN_POINT('',(-7.96428403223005,-0.757620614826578,0.0217079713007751));
#594=CARTESIAN_POINT('',(-7.96992708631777,-0.695846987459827,0.0416388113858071));
#595=CARTESIAN_POINT('',(-7.97985505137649,-0.570821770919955,0.076970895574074));
#596=CARTESIAN_POINT('',(-7.98413801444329,-0.507568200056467,0.0923656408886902));
#597=CARTESIAN_POINT('',(-7.99121566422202,-0.38016762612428,0.117935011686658));
#598=CARTESIAN_POINT('',(-7.99401601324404,-0.316024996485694,0.128129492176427));
#599=CARTESIAN_POINT('',(-7.99807212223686,-0.18708241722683,0.142930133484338));
#600=CARTESIAN_POINT('',(-7.99932879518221,-0.122282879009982,0.147539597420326));
#601=CARTESIAN_POINT('',(-8.00026256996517,0.00793126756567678,0.150962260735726));
#602=CARTESIAN_POINT('',(-7.99992883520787,0.0733470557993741,0.149735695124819));
#603=CARTESIAN_POINT('',(-7.99767082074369,0.203790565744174,0.141469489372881));
#604=CARTESIAN_POINT('',(-7.99574572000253,0.268818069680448,0.134426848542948));
#605=CARTESIAN_POINT('',(-7.98766808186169,0.46231846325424,0.105052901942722));
#606=CARTESIAN_POINT('',(-7.97921517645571,0.589546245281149,0.0744818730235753));
#607=CARTESIAN_POINT('',(-7.96654208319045,0.731113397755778,0.0297269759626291));
#608=CARTESIAN_POINT('',(-7.96490778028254,0.748703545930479,0.0239700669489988));
#609=CARTESIAN_POINT('',(-7.96153628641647,0.783738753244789,0.0121285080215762));
#610=CARTESIAN_POINT('',(-7.95979922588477,0.801183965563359,0.00604427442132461));
#611=CARTESIAN_POINT('',(-7.95801090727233,0.818573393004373,-0.000200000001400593));
#612=B_SPLINE_CURVE_WITH_KNOTS('',3,(#592,#593,#594,#595,#596,#597,#598,#599,#600,#601,#602,
#603,#604,#605,#606,#607,#608,#609,#610,#611),.UNSPECIFIED.,.F.,.F.,(4,2,2,2,2,2,2,2,2,4),(0.,
0.195246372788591,0.390771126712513,0.585543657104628,0.780200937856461,0.97618644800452,
1.17227313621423,1.56344946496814,1.61919338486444,1.67486800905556),.UNSPECIFIED.);
#613=EDGE_CURVE('E305',#121,#112,#612,.T.);
#614=ORIENTED_EDGE('',*,*,#613,.T.);
#615=ORIENTED_EDGE('',*,*,#113,.F.);
#616=CARTESIAN_POINT('',(-5.19087545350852,6.08726638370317,-0.302878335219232));
#617=CARTESIAN_POINT('',(-5.15219986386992,6.12024568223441,-0.273498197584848));
#618=CARTESIAN_POINT('',(-5.11283606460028,6.15317759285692,-0.244964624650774));
#619=CARTESIAN_POINT('',(-5.03261467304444,6.21896164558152,-0.189889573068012));
#620=CARTESIAN_POINT('',(-4.99175599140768,6.25181371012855,-0.163349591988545));
#621=CARTESIAN_POINT('',(-4.86595890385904,6.35090031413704,-0.0866907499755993));
#622=CARTESIAN_POINT('',(-4.77862285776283,6.41695918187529,-0.0401758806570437));
#623=CARTESIAN_POINT('',(-4.58842376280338,6.55449182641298,0.0436429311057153));
#624=CARTESIAN_POINT('',(-4.4848759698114,6.62587126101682,0.0796205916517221));
#625=CARTESIAN_POINT('',(-4.32468685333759,6.73061311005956,0.117971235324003));
#626=CARTESIAN_POINT('',(-4.27058825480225,6.76507492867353,0.128147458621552));
#627=CARTESIAN_POINT('',(-4.1610173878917,6.83301413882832,0.1429313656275));
#628=CARTESIAN_POINT('',(-4.10554526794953,6.86649163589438,0.14753964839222));
#629=CARTESIAN_POINT('',(-3.99330982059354,6.93236869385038,0.150961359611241));
#630=CARTESIAN_POINT('',(-3.93654054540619,6.96476009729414,0.149737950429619));
#631=CARTESIAN_POINT('',(-3.82256198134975,7.02796401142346,0.141489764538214));
#632=CARTESIAN_POINT('',(-3.7653526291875,7.05877628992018,0.134464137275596));
#633=CARTESIAN_POINT('',(-3.59369470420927,7.14856426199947,0.105116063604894));
#634=CARTESIAN_POINT('',(-3.47918206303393,7.2049111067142,0.0745231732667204));
#635=CARTESIAN_POINT('',(-3.334041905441,7.27223749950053,0.0241519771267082));
#636=CARTESIAN_POINT('',(-3.3020164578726,7.28683190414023,0.0122968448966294));
#637=CARTESIAN_POINT('',(-3.17647253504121,7.34305934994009,-0.036859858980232));
#638=CARTESIAN_POINT('',(-3.08378375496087,7.3824106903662,-0.0790420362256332));
#639=CARTESIAN_POINT('',(-2.90065625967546,7.45627111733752,-0.171729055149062));
#640=CARTESIAN_POINT('',(-2.8102204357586,7.49077422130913,-0.222244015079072));
#641=CARTESIAN_POINT('',(-2.63090380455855,7.55562625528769,-0.329792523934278));
#642=CARTESIAN_POINT('',(-2.54203732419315,7.58594605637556,-0.386867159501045));
#643=CARTESIAN_POINT('',(-2.366248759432,7.64260370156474,-0.505630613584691));
#644=CARTESIAN_POINT('',(-2.27932569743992,7.66894358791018,-0.567317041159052));
#645=CARTESIAN_POINT('',(-2.0943328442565,7.72167973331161,-0.703553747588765));
#646=CARTESIAN_POINT('',(-1.99651180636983,7.74751030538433,-0.7786587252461));
#647=CARTESIAN_POINT('',(-1.85156660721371,7.78293871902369,-0.893428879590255));
#648=CARTESIAN_POINT('',(-1.80380874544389,7.79414225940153,-0.931819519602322));
#649=CARTESIAN_POINT('',(-1.708662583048,7.81555168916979,-1.00932145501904));
#650=CARTESIAN_POINT('',(-1.66127424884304,7.82575767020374,-1.04843268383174));
#651=CARTESIAN_POINT('',(-1.61404589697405,7.83548695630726,-1.08785541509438));
#652=B_SPLINE_CURVE_WITH_KNOTS('',3,(#616,#617,#618,#619,#620,#621,#622,#623,#624,#625,#626,
#627,#628,#629,#630,#631,#632,#633,#634,#635,#636,#637,#638,#639,#640,#641,#642,#643,#644,#645,
#646,#647,#648,#649,#650,#651),.UNSPECIFIED.,.F.,.F.,(4,2,2,2,2,2,2,2,2,2,2,2,2,2,2,2,2,4),(0.,
0.176112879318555,0.352356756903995,0.708612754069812,1.09933102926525,1.2939408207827,
1.48852967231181,1.68434932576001,1.88019768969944,2.2717772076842,2.3831901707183,
2.71002334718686,3.03725634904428,3.36666387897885,3.69590179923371,4.07374262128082,
4.26060579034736,4.4474517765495),.UNSPECIFIED.);
#653=EDGE_CURVE('E309',#110,#177,#652,.T.);
#654=ORIENTED_EDGE('',*,*,#653,.T.);
#655=ORIENTED_EDGE('',*,*,#178,.F.);
#656=CARTESIAN_POINT('',(1.61404589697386,7.8354869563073,-1.0878554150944));
#657=CARTESIAN_POINT('',(1.66747328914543,7.8244802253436,-1.04325974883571));
#658=CARTESIAN_POINT('',(1.72110439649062,7.81286430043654,-0.999061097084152));
#659=CARTESIAN_POINT('',(1.8288527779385,7.78834732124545,-0.911598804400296));
#660=CARTESIAN_POINT('',(1.88297015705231,7.77544598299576,-0.868335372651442));
#661=CARTESIAN_POINT('',(2.0466654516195,7.73458880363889,-0.739771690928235));
#662=CARTESIAN_POINT('',(2.15706592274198,7.70458600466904,-0.656136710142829));
#663=CARTESIAN_POINT('',(2.38085777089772,7.63840094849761,-0.494994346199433));
#664=CARTESIAN_POINT('',(2.49425483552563,7.60220610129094,-0.417499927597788));
#665=CARTESIAN_POINT('',(2.72430915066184,7.52282580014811,-0.271811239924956));
#666=CARTESIAN_POINT('',(2.84095829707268,7.47965662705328,-0.203595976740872));
#667=CARTESIAN_POINT('',(3.01054736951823,7.41212600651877,-0.115689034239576));
#668=CARTESIAN_POINT('',(3.0619425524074,7.39105212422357,-0.0904850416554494));
#669=CARTESIAN_POINT('',(3.16547268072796,7.34730937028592,-0.0430104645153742));
#670=CARTESIAN_POINT('',(3.21760841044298,7.32463868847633,-0.0207432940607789));
#671=CARTESIAN_POINT('',(3.38189330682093,7.25105124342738,0.043551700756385));
#672=CARTESIAN_POINT('',(3.49530106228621,7.19715843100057,0.0794843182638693));
#673=CARTESIAN_POINT('',(3.66600821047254,7.11086983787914,0.117871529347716));
#674=CARTESIAN_POINT('',(3.72300767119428,7.0811999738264,0.128081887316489));
#675=CARTESIAN_POINT('',(3.83684264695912,7.02017099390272,0.1429139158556));
#676=CARTESIAN_POINT('',(3.89367818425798,6.98881211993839,0.147536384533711));
#677=CARTESIAN_POINT('',(4.00697179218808,6.92448116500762,0.150962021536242));
#678=CARTESIAN_POINT('',(4.06342675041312,6.89150207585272,0.149737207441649));
#679=CARTESIAN_POINT('',(4.17518918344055,6.82437221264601,0.141482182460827));
#680=CARTESIAN_POINT('',(4.23049648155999,6.79022126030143,0.134451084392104));
#681=CARTESIAN_POINT('',(4.39406237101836,6.68646529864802,0.105095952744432));
#682=CARTESIAN_POINT('',(4.50007741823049,6.61549313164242,0.0745125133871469));
#683=CARTESIAN_POINT('',(4.63092202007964,6.52348325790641,0.0241512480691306));
#684=CARTESIAN_POINT('',(4.65957473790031,6.50304486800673,0.0122950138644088));
#685=CARTESIAN_POINT('',(4.77777589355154,6.4175646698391,-0.0398267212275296));
#686=CARTESIAN_POINT('',(4.86445619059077,6.35203767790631,-0.0858781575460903));
#687=CARTESIAN_POINT('',(5.03207946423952,6.22009747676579,-0.187821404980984));
#688=CARTESIAN_POINT('',(5.11298976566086,6.15368141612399,-0.243763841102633));
#689=CARTESIAN_POINT('',(5.19087545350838,6.08726638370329,-0.30287833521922));
#690=B_SPLINE_CURVE_WITH_KNOTS('',3,(#656,#657,#658,#659,#660,#661,#662,#663,#664,#665,#666,
#667,#668,#669,#670,#671,#672,#673,#674,#675,#676,#677,#678,#679,#680,#681,#682,#683,#684,#685,
#686,#687,#688,#689),.UNSPECIFIED.,.F.,.F.,(4,2,2,2,2,2,2,2,2,2,2,2,2,2,2,2,4),(0.,
0.211366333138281,0.422779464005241,0.847670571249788,1.2734360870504,1.69822168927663,
1.88112692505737,2.06424295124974,2.4542309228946,2.64921010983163,2.84416144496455,
3.04004666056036,3.23596181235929,3.62740930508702,3.73882226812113,4.09215764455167,
4.44735680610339),.UNSPECIFIED.);
#691=EDGE_CURVE('E346',#173,#164,#690,.T.);
#692=ORIENTED_EDGE('',*,*,#691,.T.);
#693=ORIENTED_EDGE('',*,*,#165,.F.);
#694=CARTESIAN_POINT('',(7.95801090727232,0.818573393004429,-0.000200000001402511));
#695=CARTESIAN_POINT('',(7.9642840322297,0.757620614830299,0.0217079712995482));
#696=CARTESIAN_POINT('',(7.96992708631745,0.695846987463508,0.0416388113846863));
#697=CARTESIAN_POINT('',(7.97985505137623,0.570821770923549,0.0769708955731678));
#698=CARTESIAN_POINT('',(7.98413801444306,0.507568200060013,0.0923656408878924));
#699=CARTESIAN_POINT('',(7.99121566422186,0.380167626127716,0.117935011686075));
#700=CARTESIAN_POINT('',(7.9940160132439,0.316024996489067,0.128129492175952));
#701=CARTESIAN_POINT('',(7.99807212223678,0.187082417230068,0.142930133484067));
#702=CARTESIAN_POINT('',(7.99932879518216,0.122282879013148,0.147539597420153));
#703=CARTESIAN_POINT('',(8.00026256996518,-0.0079312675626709,0.150962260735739));
#704=CARTESIAN_POINT('',(7.99992883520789,-0.0733470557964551,0.149735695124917));
#705=CARTESIAN_POINT('',(7.99767082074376,-0.203790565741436,0.141469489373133));
#706=CARTESIAN_POINT('',(7.99574572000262,-0.268818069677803,0.134426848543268));
#707=CARTESIAN_POINT('',(7.98766808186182,-0.462318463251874,0.105052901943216));
#708=CARTESIAN_POINT('',(7.97921517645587,-0.589546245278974,0.0744818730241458));
#709=CARTESIAN_POINT('',(7.96654208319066,-0.731113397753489,0.0297269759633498));
#710=CARTESIAN_POINT('',(7.96490778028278,-0.748703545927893,0.023970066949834));
#711=CARTESIAN_POINT('',(7.96153628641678,-0.783738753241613,0.0121285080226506));
#712=CARTESIAN_POINT('',(7.95979922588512,-0.801183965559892,0.00604427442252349));
#713=CARTESIAN_POINT('',(7.95801090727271,-0.818573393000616,-0.000200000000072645));
#714=B_SPLINE_CURVE_WITH_KNOTS('',3,(#694,#695,#696,#697,#698,#699,#700,#701,#702,#703,#704,
#705,#706,#707,#708,#709,#710,#711,#712,#713),.UNSPECIFIED.,.F.,.F.,(4,2,2,2,2,2,2,2,2,4),(0.,
0.19524637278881,0.390771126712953,0.585543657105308,0.780200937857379,0.976186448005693,
1.17227313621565,1.56344946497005,1.6191933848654,1.67486800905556),.UNSPECIFIED.);
#715=EDGE_CURVE('E373',#160,#151,#714,.T.);
#716=ORIENTED_EDGE('',*,*,#715,.T.);
#717=ORIENTED_EDGE('',*,*,#152,.F.);
#718=CARTESIAN_POINT('',(5.19087545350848,-6.08726638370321,-0.302878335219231));
#719=CARTESIAN_POINT('',(5.15219986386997,-6.12024568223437,-0.273498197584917));
#720=CARTESIAN_POINT('',(5.11283606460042,-6.1531775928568,-0.244964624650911));
#721=CARTESIAN_POINT('',(5.03261467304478,-6.21896164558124,-0.189889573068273));
#722=CARTESIAN_POINT('',(4.99175599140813,-6.25181371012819,-0.163349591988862));
#723=CARTESIAN_POINT('',(4.86595890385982,-6.35090031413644,-0.0866907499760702));
#724=CARTESIAN_POINT('',(4.77862285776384,-6.41695918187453,-0.0401758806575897));
#725=CARTESIAN_POINT('',(4.58842376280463,-6.5544918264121,0.0436429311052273));
#726=CARTESIAN_POINT('',(4.48487596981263,-6.62587126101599,0.079620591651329));
#727=CARTESIAN_POINT('',(4.32468685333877,-6.73061311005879,0.117971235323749));
#728=CARTESIAN_POINT('',(4.27058825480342,-6.76507492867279,0.128147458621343));
#729=CARTESIAN_POINT('',(4.16101738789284,-6.83301413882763,0.14293136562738));
#730=CARTESIAN_POINT('',(4.10554526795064,-6.86649163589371,0.147539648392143));
#731=CARTESIAN_POINT('',(3.9933098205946,-6.93236869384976,0.150961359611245));
#732=CARTESIAN_POINT('',(3.93654054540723,-6.96476009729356,0.149737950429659));
#733=CARTESIAN_POINT('',(3.82256198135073,-7.02796401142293,0.141489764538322));
#734=CARTESIAN_POINT('',(3.76535262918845,-7.05877628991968,0.134464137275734));
#735=CARTESIAN_POINT('',(3.59369470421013,-7.14856426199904,0.105116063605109));
#736=CARTESIAN_POINT('',(3.47918206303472,-7.20491110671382,0.0745231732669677));
#737=CARTESIAN_POINT('',(3.33404190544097,-7.27223749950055,0.0241519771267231));
#738=CARTESIAN_POINT('',(3.30201645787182,-7.28683190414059,0.0122968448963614));
#739=CARTESIAN_POINT('',(3.17647253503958,-7.3430593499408,-0.0368598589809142));
#740=CARTESIAN_POINT('',(3.08378375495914,-7.38241069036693,-0.0790420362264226));
#741=CARTESIAN_POINT('',(2.90065625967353,-7.45627111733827,-0.171729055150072));
#742=CARTESIAN_POINT('',(2.81022043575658,-7.49077422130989,-0.222244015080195));
#743=CARTESIAN_POINT('',(2.63090380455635,-7.55562625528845,-0.329792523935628));
#744=CARTESIAN_POINT('',(2.54203732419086,-7.58594605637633,-0.386867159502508));
#745=CARTESIAN_POINT('',(2.36624875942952,-7.64260370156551,-0.505630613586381));
#746=CARTESIAN_POINT('',(2.27932569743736,-7.66894358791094,-0.567317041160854));
#747=CARTESIAN_POINT('',(2.0943328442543,-7.7216797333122,-0.703553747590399));
#748=CARTESIAN_POINT('',(1.99651180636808,-7.74751030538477,-0.778658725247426));
#749=CARTESIAN_POINT('',(1.85156660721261,-7.78293871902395,-0.893428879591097));
#750=CARTESIAN_POINT('',(1.803808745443,-7.79414225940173,-0.931819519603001));
#751=CARTESIAN_POINT('',(1.70866258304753,-7.81555168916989,-1.00932145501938));
#752=CARTESIAN_POINT('',(1.66127424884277,-7.82575767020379,-1.04843268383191));
#753=CARTESIAN_POINT('',(1.61404589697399,-7.83548695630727,-1.08785541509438));
#754=B_SPLINE_CURVE_WITH_KNOTS('',3,(#718,#719,#720,#721,#722,#723,#724,#725,#726,#727,#728,
#729,#730,#731,#732,#733,#734,#735,#736,#737,#738,#739,#740,#741,#742,#743,#744,#745,#746,#747,
#748,#749,#750,#751,#752,#753),.UNSPECIFIED.,.F.,.F.,(4,2,2,2,2,2,2,2,2,2,2,2,2,2,2,2,2,4),(0.,
0.17611287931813,0.352356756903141,0.708612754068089,1.09933102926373,1.29394082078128,
1.48852967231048,1.68434932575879,1.88019768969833,2.27177720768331,2.38319017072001,
2.71002334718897,3.03725634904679,3.36666387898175,3.69590179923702,4.07374262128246,
4.26060579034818,4.4474517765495),.UNSPECIFIED.);
#755=EDGE_CURVE('E155',#147,#138,#754,.T.);
#756=ORIENTED_EDGE('',*,*,#755,.T.);
#757=ORIENTED_EDGE('',*,*,#139,.F.);
#758=CARTESIAN_POINT('',(-1.61404589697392,-7.83548695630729,-1.08785541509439));
#759=CARTESIAN_POINT('',(-1.6674732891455,-7.82448022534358,-1.0432597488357));
#760=CARTESIAN_POINT('',(-1.72110439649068,-7.81286430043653,-0.999061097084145));
#761=CARTESIAN_POINT('',(-1.82885277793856,-7.78834732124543,-0.91159880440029));
#762=CARTESIAN_POINT('',(-1.88297015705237,-7.77544598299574,-0.868335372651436));
#763=CARTESIAN_POINT('',(-2.04666545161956,-7.73458880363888,-0.73977169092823));
#764=CARTESIAN_POINT('',(-2.15706592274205,-7.70458600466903,-0.656136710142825));
#765=CARTESIAN_POINT('',(-2.38085777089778,-7.63840094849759,-0.494994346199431));
#766=CARTESIAN_POINT('',(-2.49425483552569,-7.60220610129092,-0.417499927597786));
#767=CARTESIAN_POINT('',(-2.7243091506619,-7.52282580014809,-0.271811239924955));
#768=CARTESIAN_POINT('',(-2.84095829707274,-7.47965662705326,-0.20359597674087));
#769=CARTESIAN_POINT('',(-3.01054736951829,-7.41212600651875,-0.115689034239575));
#770=CARTESIAN_POINT('',(-3.06194255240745,-7.39105212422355,-0.0904850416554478));
#771=CARTESIAN_POINT('',(-3.16547268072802,-7.3473093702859,-0.0430104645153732));
#772=CARTESIAN_POINT('',(-3.21760841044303,-7.32463868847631,-0.0207432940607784));
#773=CARTESIAN_POINT('',(-3.38189330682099,-7.25105124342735,0.0435517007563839));
#774=CARTESIAN_POINT('',(-3.49530106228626,-7.19715843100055,0.0794843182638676));
#775=CARTESIAN_POINT('',(-3.66600821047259,-7.11086983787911,0.117871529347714));
#776=CARTESIAN_POINT('',(-3.72300767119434,-7.08119997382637,0.128081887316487));
#777=CARTESIAN_POINT('',(-3.83684264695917,-7.02017099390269,0.142913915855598));
#778=CARTESIAN_POINT('',(-3.89367818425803,-6.98881211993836,0.14753638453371));
#779=CARTESIAN_POINT('',(-4.00697179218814,-6.92448116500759,0.15096202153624));
#780=CARTESIAN_POINT('',(-4.06342675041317,-6.89150207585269,0.149737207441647));
#781=CARTESIAN_POINT('',(-4.1751891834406,-6.82437221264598,0.141482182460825));
#782=CARTESIAN_POINT('',(-4.23049648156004,-6.7902212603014,0.1344510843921));
#783=CARTESIAN_POINT('',(-4.39406237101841,-6.68646529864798,0.105095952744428));
#784=CARTESIAN_POINT('',(-4.50007741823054,-6.61549313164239,0.074512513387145));
#785=CARTESIAN_POINT('',(-4.63092202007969,-6.52348325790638,0.0241512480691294));
#786=CARTESIAN_POINT('',(-4.65957473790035,-6.5030448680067,0.0122950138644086));
#787=CARTESIAN_POINT('',(-4.77777589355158,-6.41756466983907,-0.0398267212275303));
#788=CARTESIAN_POINT('',(-4.86445619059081,-6.35203767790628,-0.0858781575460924));
#789=CARTESIAN_POINT('',(-5.03207946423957,-6.22009747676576,-0.187821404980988));
#790=CARTESIAN_POINT('',(-5.11298976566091,-6.15368141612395,-0.243763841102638));
#791=CARTESIAN_POINT('',(-5.19087545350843,-6.08726638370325,-0.302878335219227));
#792=B_SPLINE_CURVE_WITH_KNOTS('',3,(#758,#759,#760,#761,#762,#763,#764,#765,#766,#767,#768,
#769,#770,#771,#772,#773,#774,#775,#776,#777,#778,#779,#780,#781,#782,#783,#784,#785,#786,#787,
#788,#789,#790,#791),.UNSPECIFIED.,.F.,.F.,(4,2,2,2,2,2,2,2,2,2,2,2,2,2,2,2,4),(0.,
0.21136633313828,0.422779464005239,0.847670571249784,1.2734360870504,1.69822168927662,
1.88112692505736,2.06424295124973,2.45423092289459,2.64921010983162,2.84416144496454,
3.04004666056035,3.23596181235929,3.62740930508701,3.73882226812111,4.09215764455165,
4.44735680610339),.UNSPECIFIED.);
#793=EDGE_CURVE('E142',#134,#125,#792,.T.);
#794=ORIENTED_EDGE('',*,*,#793,.T.);
#795=EDGE_LOOP('',(#591,#614,#615,#654,#655,#692,#693,#716,#717,#756,#757,#794));
#796=FACE_BOUND('',#795,.T.);
#797=ORIENTED_EDGE('',*,*,#572,.T.);
#798=EDGE_LOOP('',(#797));
#799=FACE_BOUND('',#798,.T.);
#800=ADVANCED_FACE('F161',(#796,#799),#590,.F.);
#801=CARTESIAN_POINT('',(-5.49999999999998,-9.52627944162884,0.));
#802=DIRECTION('',(0.,0.,-1.));
#803=DIRECTION('',(-1.,0.,0.));
#804=AXIS2_PLACEMENT_3D('',#801,#802,#803);
#805=CONICAL_SURFACE('',#804,3.15,0.78539816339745);
#806=CARTESIAN_POINT('',(-5.49999999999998,-9.52627944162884,1.45000000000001));
#807=DIRECTION('',(0.,0.,-1.));
#808=DIRECTION('',(-1.,0.,0.));
#809=AXIS2_PLACEMENT_3D('',#806,#807,#808);
#810=CIRCLE('',#809,1.69999999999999);
#811=CARTESIAN_POINT('',(-7.19999999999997,-9.52627944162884,1.45000000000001));
#812=VERTEX_POINT('',#811);
#813=EDGE_CURVE('E249',#812,#812,#810,.T.);
#814=ORIENTED_EDGE('',*,*,#813,.F.);
#815=EDGE_LOOP('',(#814));
#816=FACE_BOUND('',#815,.T.);
#817=ORIENTED_EDGE('',*,*,#135,.T.);
#818=ORIENTED_EDGE('',*,*,#793,.F.);
#819=EDGE_LOOP('',(#817,#818));
#820=FACE_BOUND('',#819,.T.);
#821=ADVANCED_FACE('F165',(#816,#820),#805,.F.);
#822=CARTESIAN_POINT('',(-5.49999999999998,-9.52627944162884,0.));
#823=DIRECTION('',(0.,0.,-1.));
#824=DIRECTION('',(-1.,0.,0.));
#825=AXIS2_PLACEMENT_3D('',#822,#823,#824);
#826=CYLINDRICAL_SURFACE('',#825,1.69999999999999);
#827=ORIENTED_EDGE('',*,*,#561,.F.);
#828=EDGE_LOOP('',(#827));
#829=FACE_BOUND('',#828,.T.);
#830=ORIENTED_EDGE('',*,*,#813,.T.);
#831=EDGE_LOOP('',(#830));
#832=FACE_BOUND('',#831,.T.);
#833=ADVANCED_FACE('F169',(#829,#832),#826,.F.);
#834=CARTESIAN_POINT('',(5.50000000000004,-9.5262794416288,0.));
#835=DIRECTION('',(0.,0.,-1.));
#836=DIRECTION('',(-1.,0.,0.));
#837=AXIS2_PLACEMENT_3D('',#834,#835,#836);
#838=CONICAL_SURFACE('',#837,3.15,0.785398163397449);
#839=CARTESIAN_POINT('',(5.50000000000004,-9.5262794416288,1.45000000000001));
#840=DIRECTION('',(0.,0.,-1.));
#841=DIRECTION('',(-1.,0.,0.));
#842=AXIS2_PLACEMENT_3D('',#839,#840,#841);
#843=CIRCLE('',#842,1.69999999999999);
#844=CARTESIAN_POINT('',(3.80000000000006,-9.5262794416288,1.45000000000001));
#845=VERTEX_POINT('',#844);
#846=EDGE_CURVE('E240',#845,#845,#843,.T.);
#847=ORIENTED_EDGE('',*,*,#846,.F.);
#848=EDGE_LOOP('',(#847));
#849=FACE_BOUND('',#848,.T.);
#850=ORIENTED_EDGE('',*,*,#148,.T.);
#851=ORIENTED_EDGE('',*,*,#755,.F.);
#852=EDGE_LOOP('',(#850,#851));
#853=FACE_BOUND('',#852,.T.);
#854=ADVANCED_FACE('F173',(#849,#853),#838,.F.);
#855=CARTESIAN_POINT('',(5.50000000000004,-9.5262794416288,0.));
#856=DIRECTION('',(0.,0.,-1.));
#857=DIRECTION('',(-1.,0.,0.));
#858=AXIS2_PLACEMENT_3D('',#855,#856,#857);
#859=CYLINDRICAL_SURFACE('',#858,1.69999999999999);
#860=ORIENTED_EDGE('',*,*,#550,.F.);
#861=EDGE_LOOP('',(#860));
#862=FACE_BOUND('',#861,.T.);
#863=ORIENTED_EDGE('',*,*,#846,.T.);
#864=EDGE_LOOP('',(#863));
#865=FACE_BOUND('',#864,.T.);
#866=ADVANCED_FACE('F171',(#862,#865),#859,.F.);
#867=CARTESIAN_POINT('',(11.,0.,0.));
#868=DIRECTION('',(0.,0.,-1.));
#869=DIRECTION('',(-1.,0.,0.));
#870=AXIS2_PLACEMENT_3D('',#867,#868,#869);
#871=CONICAL_SURFACE('',#870,3.15,0.78539816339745);
#872=CARTESIAN_POINT('',(11.,0.,1.45000000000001));
#873=DIRECTION('',(0.,0.,-1.));
#874=DIRECTION('',(-1.,0.,0.));
#875=AXIS2_PLACEMENT_3D('',#872,#873,#874);
#876=CIRCLE('',#875,1.69999999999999);
#877=CARTESIAN_POINT('',(9.30000000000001,0.,1.45000000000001));
#878=VERTEX_POINT('',#877);
#879=EDGE_CURVE('E232',#878,#878,#876,.T.);
#880=ORIENTED_EDGE('',*,*,#879,.F.);
#881=EDGE_LOOP('',(#880));
#882=FACE_BOUND('',#881,.T.);
#883=ORIENTED_EDGE('',*,*,#161,.T.);
#884=ORIENTED_EDGE('',*,*,#715,.F.);
#885=EDGE_LOOP('',(#883,#884));
#886=FACE_BOUND('',#885,.T.);
#887=ADVANCED_FACE('F368',(#882,#886),#871,.F.);
#888=CARTESIAN_POINT('',(11.,0.,0.));
#889=DIRECTION('',(0.,0.,-1.));
#890=DIRECTION('',(-1.,0.,0.));
#891=AXIS2_PLACEMENT_3D('',#888,#889,#890);
#892=CYLINDRICAL_SURFACE('',#891,1.69999999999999);
#893=ORIENTED_EDGE('',*,*,#539,.F.);
#894=EDGE_LOOP('',(#893));
#895=FACE_BOUND('',#894,.T.);
#896=ORIENTED_EDGE('',*,*,#879,.T.);
#897=EDGE_LOOP('',(#896));
#898=FACE_BOUND('',#897,.T.);
#899=ADVANCED_FACE('F363',(#895,#898),#892,.F.);
#900=CARTESIAN_POINT('',(5.49999999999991,9.52627944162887,0.));
#901=DIRECTION('',(0.,0.,-1.));
#902=DIRECTION('',(-1.,0.,0.));
#903=AXIS2_PLACEMENT_3D('',#900,#901,#902);
#904=CONICAL_SURFACE('',#903,3.15,0.78539816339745);
#905=CARTESIAN_POINT('',(5.49999999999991,9.52627944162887,1.45000000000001));
#906=DIRECTION('',(0.,0.,-1.));
#907=DIRECTION('',(-1.,0.,0.));
#908=AXIS2_PLACEMENT_3D('',#905,#906,#907);
#909=CIRCLE('',#908,1.69999999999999);
#910=CARTESIAN_POINT('',(3.79999999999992,9.52627944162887,1.45000000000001));
#911=VERTEX_POINT('',#910);
#912=EDGE_CURVE('E224',#911,#911,#909,.T.);
#913=ORIENTED_EDGE('',*,*,#912,.F.);
#914=EDGE_LOOP('',(#913));
#915=FACE_BOUND('',#914,.T.);
#916=ORIENTED_EDGE('',*,*,#174,.T.);
#917=ORIENTED_EDGE('',*,*,#691,.F.);
#918=EDGE_LOOP('',(#916,#917));
#919=FACE_BOUND('',#918,.T.);
#920=ADVANCED_FACE('F359',(#915,#919),#904,.F.);
#921=CARTESIAN_POINT('',(5.49999999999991,9.52627944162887,0.));
#922=DIRECTION('',(0.,0.,-1.));
#923=DIRECTION('',(-1.,0.,0.));
#924=AXIS2_PLACEMENT_3D('',#921,#922,#923);
#925=CYLINDRICAL_SURFACE('',#924,1.69999999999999);
#926=ORIENTED_EDGE('',*,*,#528,.F.);
#927=EDGE_LOOP('',(#926));
#928=FACE_BOUND('',#927,.T.);
#929=ORIENTED_EDGE('',*,*,#912,.T.);
#930=EDGE_LOOP('',(#929));
#931=FACE_BOUND('',#930,.T.);
#932=ADVANCED_FACE('F355',(#928,#931),#925,.F.);
#933=CARTESIAN_POINT('',(-5.50000000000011,9.52627944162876,0.));
#934=DIRECTION('',(0.,0.,-1.));
#935=DIRECTION('',(-1.,0.,0.));
#936=AXIS2_PLACEMENT_3D('',#933,#934,#935);
#937=CONICAL_SURFACE('',#936,3.15,0.78539816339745);
#938=CARTESIAN_POINT('',(-5.50000000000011,9.52627944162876,1.45000000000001));
#939=DIRECTION('',(0.,0.,-1.));
#940=DIRECTION('',(-1.,0.,0.));
#941=AXIS2_PLACEMENT_3D('',#938,#939,#940);
#942=CIRCLE('',#941,1.69999999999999);
#943=CARTESIAN_POINT('',(-7.2000000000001,9.52627944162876,1.45000000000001));
#944=VERTEX_POINT('',#943);
#945=EDGE_CURVE('E216',#944,#944,#942,.T.);
#946=ORIENTED_EDGE('',*,*,#945,.F.);
#947=EDGE_LOOP('',(#946));
#948=FACE_BOUND('',#947,.T.);
#949=ORIENTED_EDGE('',*,*,#185,.T.);
#950=ORIENTED_EDGE('',*,*,#653,.F.);
#951=EDGE_LOOP('',(#949,#950));
#952=FACE_BOUND('',#951,.T.);
#953=ADVANCED_FACE('F351',(#948,#952),#937,.F.);
#954=CARTESIAN_POINT('',(-5.50000000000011,9.52627944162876,0.));
#955=DIRECTION('',(0.,0.,-1.));
#956=DIRECTION('',(-1.,0.,0.));
#957=AXIS2_PLACEMENT_3D('',#954,#955,#956);
#958=CYLINDRICAL_SURFACE('',#957,1.69999999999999);
#959=ORIENTED_EDGE('',*,*,#517,.F.);
#960=EDGE_LOOP('',(#959));
#961=FACE_BOUND('',#960,.T.);
#962=ORIENTED_EDGE('',*,*,#945,.T.);
#963=EDGE_LOOP('',(#962));
#964=FACE_BOUND('',#963,.T.);
#965=ADVANCED_FACE('F334',(#961,#964),#958,.F.);
#966=CARTESIAN_POINT('',(-11.,0.,0.));
#967=DIRECTION('',(0.,0.,-1.));
#968=DIRECTION('',(-1.,0.,0.));
#969=AXIS2_PLACEMENT_3D('',#966,#967,#968);
#970=CONICAL_SURFACE('',#969,3.15,0.78539816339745);
#971=CARTESIAN_POINT('',(-11.,0.,1.45000000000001));
#972=DIRECTION('',(0.,0.,-1.));
#973=DIRECTION('',(-1.,0.,0.));
#974=AXIS2_PLACEMENT_3D('',#971,#972,#973);
#975=CIRCLE('',#974,1.69999999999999);
#976=CARTESIAN_POINT('',(-12.7,0.,1.45000000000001));
#977=VERTEX_POINT('',#976);
#978=EDGE_CURVE('E208',#977,#977,#975,.T.);
#979=ORIENTED_EDGE('',*,*,#978,.F.);
#980=EDGE_LOOP('',(#979));
#981=FACE_BOUND('',#980,.T.);
#982=ORIENTED_EDGE('',*,*,#122,.T.);
#983=ORIENTED_EDGE('',*,*,#613,.F.);
#984=EDGE_LOOP('',(#982,#983));
#985=FACE_BOUND('',#984,.T.);
#986=ADVANCED_FACE('F330',(#981,#985),#970,.F.);
#987=CARTESIAN_POINT('',(-11.,0.,0.));
#988=DIRECTION('',(0.,0.,-1.));
#989=DIRECTION('',(-1.,0.,0.));
#990=AXIS2_PLACEMENT_3D('',#987,#988,#989);
#991=CYLINDRICAL_SURFACE('',#990,1.69999999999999);
#992=ORIENTED_EDGE('',*,*,#506,.F.);
#993=EDGE_LOOP('',(#992));
#994=FACE_BOUND('',#993,.T.);
#995=ORIENTED_EDGE('',*,*,#978,.T.);
#996=EDGE_LOOP('',(#995));
#997=FACE_BOUND('',#996,.T.);
#998=ADVANCED_FACE('F285',(#994,#997),#991,.F.);
#999=CARTESIAN_POINT('',(0.,0.,2.032));
#1000=DIRECTION('',(0.,0.,-1.));
#1001=DIRECTION('',(-1.,0.,0.));
#1002=AXIS2_PLACEMENT_3D('',#999,#1000,#1001);
#1003=PLANE('',#1002);
#1004=DIRECTION('',(-0.707106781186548,-0.707106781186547,0.));
#1005=VECTOR('',#1004,1.);
#1006=CARTESIAN_POINT('',(-15.2664354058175,15.2664354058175,2.032));
#1007=LINE('',#1006,#1005);
#1008=EDGE_CURVE('E124',#62,#40,#1007,.T.);
#1009=ORIENTED_EDGE('',*,*,#1008,.F.);
#1010=ORIENTED_EDGE('',*,*,#65,.T.);
#1011=DIRECTION('',(-0.707106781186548,0.707106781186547,0.));
#1012=VECTOR('',#1011,1.);
#1013=CARTESIAN_POINT('',(15.2664354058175,15.2664354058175,2.032));
#1014=LINE('',#1013,#1012);
#1015=EDGE_CURVE('E304',#49,#64,#1014,.T.);
#1016=ORIENTED_EDGE('',*,*,#1015,.F.);
#1017=ORIENTED_EDGE('',*,*,#50,.T.);
#1018=EDGE_LOOP('',(#1009,#1010,#1016,#1017));
#1019=FACE_BOUND('',#1018,.T.);
#1020=ORIENTED_EDGE('',*,*,#210,.T.);
#1021=EDGE_LOOP('',(#1020));
#1022=FACE_BOUND('',#1021,.T.);
#1023=ORIENTED_EDGE('',*,*,#402,.T.);
#1024=EDGE_LOOP('',(#1023));
#1025=FACE_BOUND('',#1024,.T.);
#1026=CARTESIAN_POINT('',(0.,0.,2.032));
#1027=DIRECTION('',(0.,0.,-1.));
#1028=DIRECTION('',(-1.,0.,0.));
#1029=AXIS2_PLACEMENT_3D('',#1026,#1027,#1028);
#1030=CIRCLE('',#1029,18.415);
#1031=CARTESIAN_POINT('',(-18.415,0.,2.032));
#1032=VERTEX_POINT('',#1031);
#1033=EDGE_CURVE('E294',#1032,#1032,#1030,.T.);
#1034=ORIENTED_EDGE('',*,*,#1033,.F.);
#1035=EDGE_LOOP('',(#1034));
#1036=FACE_BOUND('',#1035,.T.);
#1037=ORIENTED_EDGE('',*,*,#306,.T.);
#1038=EDGE_LOOP('',(#1037));
#1039=FACE_BOUND('',#1038,.T.);
#1040=ADVANCED_FACE('F281',(#1019,#1022,#1025,#1036,#1039),#1003,.T.);
#1041=CARTESIAN_POINT('',(0.,0.,2.032));
#1042=DIRECTION('',(0.,0.,-1.));
#1043=DIRECTION('',(-1.,0.,0.));
#1044=AXIS2_PLACEMENT_3D('',#1041,#1042,#1043);
#1045=CYLINDRICAL_SURFACE('',#1044,18.415);
#1046=CARTESIAN_POINT('',(0.,0.,0.508000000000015));
#1047=DIRECTION('',(0.,0.,1.));
#1048=DIRECTION('',(1.,0.,0.));
#1049=AXIS2_PLACEMENT_3D('',#1046,#1047,#1048);
#1050=CIRCLE('',#1049,18.415);
#1051=CARTESIAN_POINT('',(18.415,0.,0.508000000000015));
#1052=VERTEX_POINT('',#1051);
#1053=EDGE_CURVE('E13',#1052,#1052,#1050,.T.);
#1054=ORIENTED_EDGE('',*,*,#1053,.T.);
#1055=EDGE_LOOP('',(#1054));
#1056=FACE_BOUND('',#1055,.T.);
#1057=ORIENTED_EDGE('',*,*,#1033,.T.);
#1058=EDGE_LOOP('',(#1057));
#1059=FACE_BOUND('',#1058,.T.);
#1060=ADVANCED_FACE('F284',(#1056,#1059),#1045,.T.);
#1061=CARTESIAN_POINT('',(3.61076745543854,26.9221033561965,0.));
#1062=DIRECTION('',(-0.707106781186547,-0.707106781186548,0.));
#1063=DIRECTION('',(0.707106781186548,-0.707106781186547,0.));
#1064=AXIS2_PLACEMENT_3D('',#1061,#1062,#1063);
#1065=PLANE('',#1064);
#1066=ORIENTED_EDGE('',*,*,#494,.T.);
#1067=ORIENTED_EDGE('',*,*,#56,.F.);
#1068=ORIENTED_EDGE('',*,*,#1015,.T.);
#1069=ORIENTED_EDGE('',*,*,#83,.F.);
#1070=EDGE_LOOP('',(#1066,#1067,#1068,#1069));
#1071=FACE_BOUND('',#1070,.T.);
#1072=ADVANCED_FACE('F303',(#1071),#1065,.F.);
#1073=CARTESIAN_POINT('',(-3.61076745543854,26.9221033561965,0.));
#1074=DIRECTION('',(0.707106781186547,-0.707106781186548,0.));
#1075=DIRECTION('',(0.707106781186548,0.707106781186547,0.));
#1076=AXIS2_PLACEMENT_3D('',#1073,#1074,#1075);
#1077=PLANE('',#1076);
#1078=ORIENTED_EDGE('',*,*,#487,.T.);
#1079=ORIENTED_EDGE('',*,*,#73,.F.);
#1080=ORIENTED_EDGE('',*,*,#1008,.T.);
#1081=ORIENTED_EDGE('',*,*,#41,.F.);
#1082=EDGE_LOOP('',(#1078,#1079,#1080,#1081));
#1083=FACE_BOUND('',#1082,.T.);
#1084=ADVANCED_FACE('F122',(#1083),#1077,.F.);
#1085=CARTESIAN_POINT('',(0.,0.,0.));
#1086=DIRECTION('',(0.,0.,1.));
#1087=DIRECTION('',(1.,0.,0.));
#1088=AXIS2_PLACEMENT_3D('',#1085,#1086,#1087);
#1089=CONICAL_SURFACE('',#1088,17.907,0.785398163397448);
#1090=ORIENTED_EDGE('',*,*,#1053,.F.);
#1091=EDGE_LOOP('',(#1090));
#1092=FACE_BOUND('',#1091,.T.);
#1093=ORIENTED_EDGE('',*,*,#100,.F.);
#1094=EDGE_LOOP('',(#1093));
#1095=FACE_BOUND('',#1094,.T.);
#1096=ADVANCED_FACE('F315',(#1092,#1095),#1089,.T.);
#1097=CLOSED_SHELL('',(#60,#87,#189,#285,#381,#477,#585,#800,#821,#833,#854,#866,#887,#899,#920,
#932,#953,#965,#986,#998,#1040,#1060,#1072,#1084,#1096));
#1098=MANIFOLD_SOLID_BREP('B2',#1097);
#1099=ADVANCED_BREP_SHAPE_REPRESENTATION('',(#18,#1098),#14);
#1100=SHAPE_DEFINITION_REPRESENTATION(#9,#1099);
ENDSEC;
END-ISO-10303-21;
